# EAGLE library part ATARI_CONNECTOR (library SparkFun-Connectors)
DB9 labeled for Atari joystick

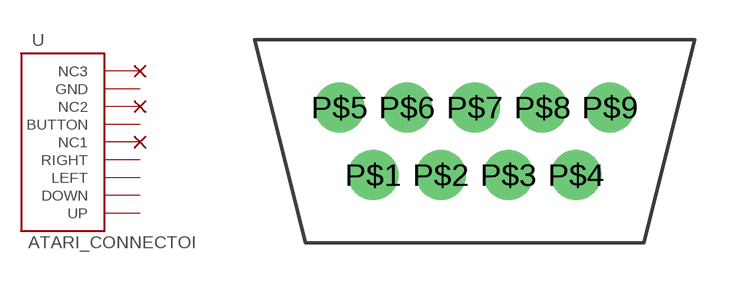
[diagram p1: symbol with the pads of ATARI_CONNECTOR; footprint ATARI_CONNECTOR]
Designator prefix -

## ATARI_CONNECTOR  [ATARI_CONNECTOR]
P$1  BUTTON
P$2  NC2
P$3  GND
P$4  NC3
P$5  UP
P$6  DOWN
P$7  LEFT
P$8  RIGHT
P$9  NC1

## Footprint ATARI_CONNECTOR (pad centres in mm)
drill 0.8 pad 1.88: P$1 1.27,2.54; P$2 3.81,2.54; P$3 6.35,2.54; P$4 8.89,2.54; P$5 0,5.08; P$6 2.54,5.08; P$7 5.08,5.08; P$8 7.62,5.08; P$9 10.16,5.08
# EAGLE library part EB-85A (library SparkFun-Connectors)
EB-85A Connector Proven layout and schematic for ETek 5Hz GPS receiver connector. Spark Fun Electronics SKU : GPS-08297

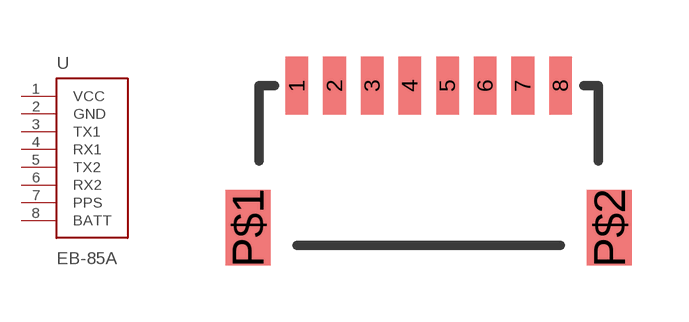
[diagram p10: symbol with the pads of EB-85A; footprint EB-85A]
Designator prefix -

## EB-85ASMD  [EB-85A]
1  VCC  pwr
2  GND  pwr
3  TX1  out
4  RX1  in
5  TX2  out
6  RX2  in
7  PPS  out
8  BATT  pwr

## Footprint EB-85A (pad centres in mm)
smd 0.6 x 1.55: 1 0,0; 2 1,0; 3 2,0; 4 3,0; 5 4,0; 6 5,0; 7 6,0; 8 7,0
smd 1.2 x 2: P$1 -1.3,-3.775; P$2 8.3,-3.775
